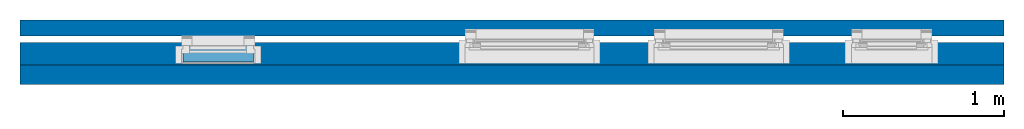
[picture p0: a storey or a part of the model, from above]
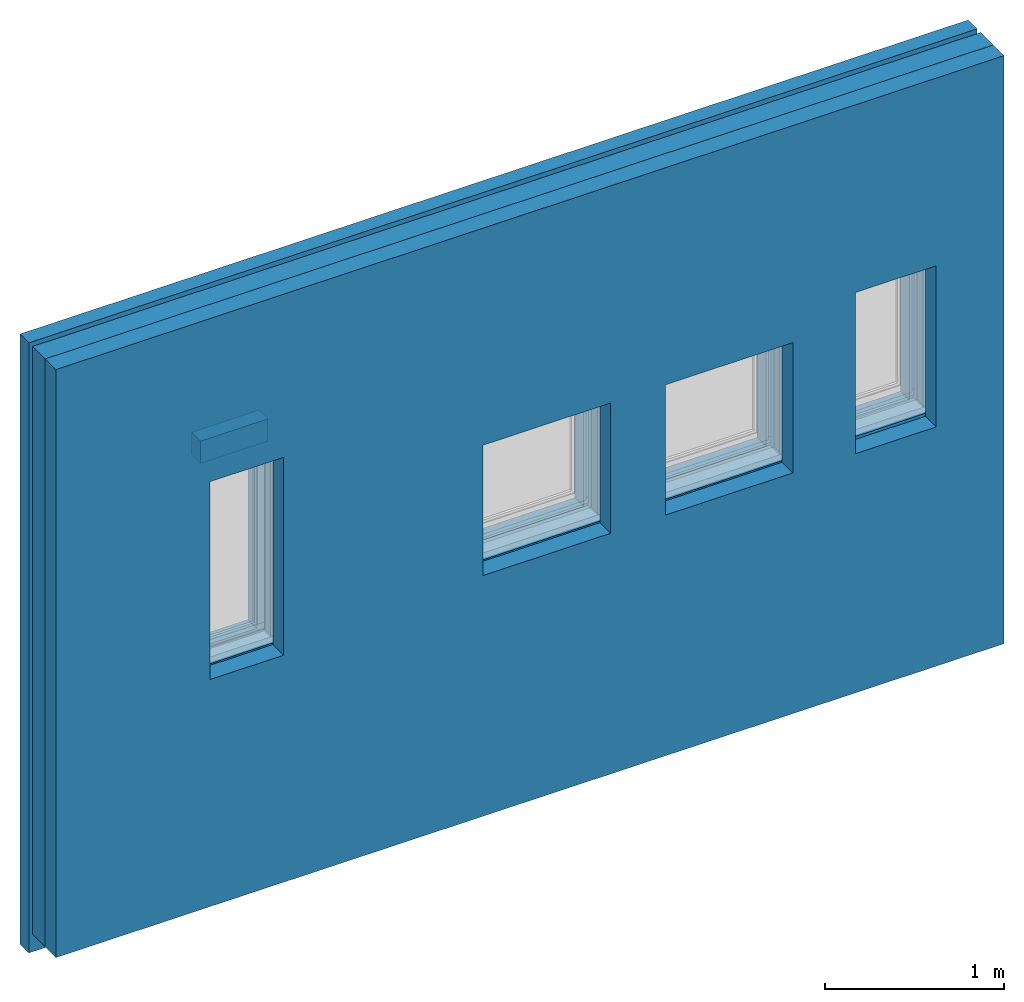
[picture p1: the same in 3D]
Properties of the parts of a building model (IFC2X3)

# File
Description: ViewDefinition [CoordinationView_V2.0]
File name: 0001
Time: 2018-10-30T14:35:21
Written by: The EXPRESS Data Manager Version 5.02.0100.07 : 28 Aug 2013
Made in: 20180328_1600(x64) - Exporter 19.1.0.0 - Alternate UI 19.1.0.0
Comment: STEP Physical File produced by: The EXPRESS Data Manager Version 5.02.0100.07 : 28 Aug 2013 * Module: EDMstepFileFactory/EDMstandAlone * Creation date: Tue Oct 30 14:35:21 2018 * Host: DESKTOP-FDA31SE * Database: C:\Users\marti\AppData\Local\Temp\{E08C83BA-BC12-497E-8B5D-7DDBD25FC910}\ifc * Database version: 5507 * Database creation date: Tue Oct 30 14:35:19 2018 * Schema: IFC2X3 * Model: DataRepository.ifc * Model creation date: Tue Oct 30 14:35:19 2018 * Header model: DataRepository.ifc_HeaderModel * Header model creation date: Tue Oct 30 14:35:20 2018 * EDMuser: sdai-user * EDMgroup: sdai-group * License ID and type: 5605 : Permanent license. Expiry date: * EDMstepFileFactory options: 020000

# IfcProject, 0001
LongName: Project Name; Phase: Project Status

# IfcSite, Default
RefLatitude: 42, 21, 31, 181945; RefLongitude: -71, -3, -24, -263305; RefElevation: 0 mm

# IfcBuilding
Pset_BuildingCommon - NumberOfStoreys: 1
Pset_ProductRequirements - Category: Project Information

# IfcBuildingStorey: Level:8mm Head, Level 1
LongName: Level 1; Elevation: 0 mm
Pset_AirSideSystemInformation - Name: Level 1
Pset_ProductRequirements - Name: Level 1; Category: Levels

# IfcElementAssembly: NLRS_31_WI_H11_A1vg_GM:455 breed, NLRS_31_WI_H11_A1vg_GM:455 breed:395825
In: Level 1
Classification: 31.22.21 (Uniformat); Group: Model Group:NLRS_31_WI_H11_A1vg_GM - 455 breed:418941
Pset_ProductRequirements - Category: Windows
Pset_QuantityTakeOff - Reference: 455 breed

# IfcElementAssembly: Windows Assembly:NLRS_31_WI_H11-A1dr-GM_sh_gen_TOBA-JM - Kozijn tbv IFC 800x800, Windows Assembly:NLRS_31_WI_H11-A1dr-GM_sh_gen_TOBA-JM - Kozijn tbv IFC 800x800:418976
In: Level 1
PredefinedType: USERDEFINED
Pset_ProductRequirements - Category: Assemblies
Pset_QuantityTakeOff - Reference: NLRS_31_WI_H11-A1dr-GM_sh_gen_TOBA-JM - Kozijn tbv IFC 800x800

# IfcOpeningElement: Opening (12)
In: Level 1
Pset_ElementShading - Roughness: 304.8 mm
Pset_ManufacturerTypeInformation - Manufacturer: TOBA b.v.
Pset_ProductRequirements - Category: Walls
Pset_QuantityTakeOff - sets with these values: 2
Name (Basic Wall:...) | Classification | Reference
4 x NLRS_21_WA_metselwerk bestaand 100mm:343451 | 21.11 buitenwanden; niet constructief, massieve wanden (Uniformat) | NLRS_21_WA_metselwerk bestaand 100mm
4 x NLRS_21_WA_isolatie_EPS 140mm:343452 | 21.00 (Uniformat) | NLRS_21_WA_isolatie_EPS 140mm
4 x NLRS_21_WA_kalkzandsteen CS12 120mm:359981 | 21.21 buitenwanden; constructief, massieve wanden (Uniformat) | NLRS_21_WA_kalkzandsteen CS12 120mm

# IfcWallStandardCase: Basic Wall:NLRS_21_WA_isolatie_EPS 140mm, Basic Wall:NLRS_21_WA_isolatie_EPS 140mm:343452
In: Level 1
Type - PredefinedType: STANDARD; Material: NLRS_n7_isolatie_EPS_140mm 140 mm
Type - Pset_ElementShading - Roughness: 304.8 mm
Type - Pset_ManufacturerTypeInformation - Manufacturer: TOBA b.v.
Type - Pset_ProductRequirements - Category: Walls
Type - Pset_QuantityTakeOff - Reference: NLRS_21_WA_isolatie_EPS 140mm
Type - Pset_ReinforcementBarPitchOfWall - Description: isolatie, EPS; Reference: NLRS_21_WA_isolatie_EPS 140mm
Type - Pset_WallCommon - IsExternal: no; Reference: NLRS_21_WA_isolatie_EPS 140mm; ThermalTransmittance: 0.25 kg/K/s3
Classification: 21.00 (Uniformat)
Pset_WallCommon - IsExternal: yes; ExtendToStructure: no; LoadBearing: no

# IfcWallStandardCase: Basic Wall:NLRS_21_WA_kalkzandsteen CS12 120mm, Basic Wall:NLRS_21_WA_kalkzandsteen CS12 120mm:359981
In: Level 1
Type - PredefinedType: STANDARD; Material: NLRS_f1_kalkzandsteen_CS12 120 mm
Type - Pset_ElementShading - Roughness: 304.8 mm
Type - Pset_ManufacturerTypeInformation - Manufacturer: TOBA b.v.
Type - Pset_ProductRequirements - Category: Walls
Type - Pset_QuantityTakeOff - Reference: NLRS_21_WA_kalkzandsteen CS12 120mm
Type - Pset_ReinforcementBarPitchOfWall - Description: binnenspouwblad kalkzandsteen; Reference: NLRS_21_WA_kalkzandsteen CS12 120mm
Type - Pset_WallCommon - IsExternal: no; Reference: NLRS_21_WA_kalkzandsteen CS12 120mm; ThermalTransmittance: 7.16667 kg/K/s3
Classification: 21.21 buitenwanden; constructief, massieve wanden (Uniformat)
Pset_WallCommon - IsExternal: yes; ExtendToStructure: no; LoadBearing: no

# IfcWallStandardCase: Basic Wall:NLRS_21_WA_metselwerk bestaand 100mm, Basic Wall:NLRS_21_WA_metselwerk bestaand 100mm:343451
In: Level 1
Type - PredefinedType: STANDARD; Material: NLRS_g2_baksteen_bestaand 100 mm
Type - Pset_ElementShading - Roughness: 304.8 mm
Type - Pset_ManufacturerTypeInformation - Manufacturer: TOBA b.v.
Type - Pset_ProductRequirements - Category: Walls
Type - Pset_QuantityTakeOff - Reference: NLRS_21_WA_metselwerk bestaand 100mm
Type - Pset_ReinforcementBarPitchOfWall - Description: bestaande buitenwand, halfsteens metselwerk; Reference: NLRS_21_WA_metselwerk bestaand 100mm
Type - Pset_WallCommon - Reference: NLRS_21_WA_metselwerk bestaand 100mm; ThermalTransmittance: 4.1 kg/K/s3; IsExternal: no
Classification: 21.11 buitenwanden; niet constructief, massieve wanden (Uniformat)
Pset_WallCommon - IsExternal: yes; ExtendToStructure: no; LoadBearing: no

# IfcWindow: 17x17 (3)
In: Level 1
Type - ParameterTakesPrecedence: no; Sizeable: no; Classification: 31 Buitenwandopeningen (Uniformat); Material: NLRS_i3_meranti_draaiende_delen_geschilderd_creme_RAL7006
Pset_ProductRequirements - Category: Windows
Pset_QuantityTakeOff - Reference: 17x17
Pset_WindowCommon - IsExternal: no; Reference: 17x17
Name (NLRS_30_WIN_glaslat-raam_sh_gen_TOBA-JM:17x17:...) | OverallHeight (mm) | OverallWidth (mm)
345039 | 666 | 666
360892 | 666 | 666
360925 | 866 | 366 | Group: Model Group:NLRS_31_WI_H11-A1dr-GM_sh_gen_TOBA-JM - Raam tbv IFC Export 1000x500:418978

# IfcWindow: 43x145 (3)
In: Level 1
Type - ParameterTakesPrecedence: no; Sizeable: no; Classification: 31 Buitenwandopeningen (Uniformat); Material: NLRS_i3_hout_vuren_generiek
OverallHeight: 44.8059 mm
Pset_ProductRequirements - Category: Windows
Pset_QuantityTakeOff - Reference: 43x145
Pset_WindowCommon - IsExternal: no; Reference: 43x145
Name (NLRS_30_WIN_spouwlat_bovendorpel-zonder-bovenrek_sh_gen_TOBA-JM:43x145:...) | OverallWidth (mm)
345042 | 876
360895 | 876
360928 | 576 | Group: Model Group:NLRS_31_WI_H11-A1dr-GM_sh_gen_TOBA-JM - Raam tbv IFC Export 1000x500:418978

# IfcWindow: 53x145 (3)
In: Level 1
Type - ParameterTakesPrecedence: no; Sizeable: no; Classification: 31 Buitenwandopeningen (Uniformat); Material: NLRS_i3_hout_vuren_generiek
OverallHeight: 53 mm
Pset_ProductRequirements - Category: Windows
Pset_QuantityTakeOff - Reference: 53x145
Pset_WindowCommon - IsExternal: no; Reference: 53x145
Name (NLRS_30_WIN_spouwlat-onderdorpel_sh_gen_TOBA-JM:53x145:...) | OverallWidth (mm)
345034 | 876
360887 | 876
360920 | 576 | Group: Model Group:NLRS_31_WI_H11-A1dr-GM_sh_gen_TOBA-JM - Raam tbv IFC Export 1000x500:418978

# IfcWindow: 68x90 (3)
In: Level 1
Type - ParameterTakesPrecedence: no; Sizeable: no; Classification: 31 Buitenwandopeningen (Uniformat); Material: NLRS_i3_meranti_draaiende_delen_geschilderd_creme_RAL7006
Pset_ProductRequirements - Category: Windows
Pset_QuantityTakeOff - Reference: 68x90
Pset_WindowCommon - IsExternal: no; Reference: 68x90
Name (NLRS_30_WIN_raamhout_sh_gen_TOBA-JM:68x90:...) | OverallHeight (mm) | OverallWidth (mm)
345038 | 715 | 752
360891 | 715 | 752
360924 | 915 | 452 | Group: Model Group:NLRS_31_WI_H11-A1dr-GM_sh_gen_TOBA-JM - Raam tbv IFC Export 1000x500:418978

# IfcWindow: Type, NLRS_30_MC_aftimmering_rekje:Type:406789
In: Level 1
Type - ParameterTakesPrecedence: no; Sizeable: no; Classification: 31 Buitenwandopeningen (Uniformat); Material: NLRS_f7_gips_vertikaal
OverallHeight: 230 mm; OverallWidth: 437 mm; Group: Model Group:NLRS_31_WI_H11_A1vg_GM - 455 breed:418941
Pset_ProductRequirements - Category: Windows
Pset_QuantityTakeOff - Reference: Type
Pset_WindowCommon - IsExternal: no; Reference: Type

# IfcWindow: Type (5)
In: Level 1
Type - ParameterTakesPrecedence: no; Sizeable: no; Classification: 31 Buitenwandopeningen (Uniformat); Material: NLRS_i3_hout_vuren_generiek
Pset_ProductRequirements - Category: Windows
Pset_QuantityTakeOff - Reference: Type
Pset_WindowCommon - IsExternal: no; Reference: Type
Group: Model Group:NLRS_31_WI_H11_A1vg_GM - 455 breed:418941
Name | OverallHeight (mm) | OverallWidth (mm)
NLRS_30_MC_spouwlat_zijstijll_47x110:Type:395856 | 1527.4 | 105
NLRS_30_MC_spouwlat_onderdorpel_bis_53x110:Type:406786 | 53 | 531
NLRS_30_MC_spouwlat_zijstijll_47x110:Type:406787 | 1527.4 | 105
NLRS_30_MC_spouwlat_bovendorpel_bis_38x101:Type:406788 | 38 | 437
NLRS_30_MC_spouwlat_bovendorpel_boven_rekje_bis_45x101:Type:406790 | 45.026 | 437

# IfcWindow: Type (4)
In: Level 1
Type - ParameterTakesPrecedence: no; Sizeable: no; Classification: 31 Buitenwandopeningen (Uniformat); Material: NLRS_i3_meranti_geschilderd_RAL7006
Pset_ProductRequirements - Category: Windows
Pset_QuantityTakeOff - Reference: Type
Pset_WindowCommon - IsExternal: no; Reference: Type
Group: Model Group:NLRS_31_WI_H11_A1vg_GM - 455 breed:418941
Name | OverallHeight (mm) | OverallWidth (mm)
NLRS_30_MC_onderdorpel_bis_67x114:Type:395826 | 67 | 455
NLRS_30_MC_zijstijll_vg_bis_67x114:Type:395827 | 1274.4 | 67
NLRS_30_MC_zijstijll_vg_bis_67x114:Type:395828 | 1274.4 | 67
NLRS_30_MC_bovendorpel_vg_bis_90x114:Type:395857 | 90 | 455

# IfcWindow: aanslagprofiel (3)
In: Level 1
Type - ParameterTakesPrecedence: no; Sizeable: no; Classification: 31 Buitenwandopeningen (Uniformat); Material: NLRS_h4_aluminum_geanodizeerd_RAL7006
Pset_ProductRequirements - Category: Windows
Pset_QuantityTakeOff - Reference: aanslagprofiel
Pset_WindowCommon - IsExternal: no; Reference: aanslagprofiel
Name (NLRS_30_WIN_aanslagprofiel_sh_gen_TOBA-JM:aanslagprofiel:...) | OverallHeight (mm) | OverallWidth (mm)
345040 | 671.5 | 666
360893 | 671.5 | 666
360926 | 871.5 | 366 | Group: Model Group:NLRS_31_WI_H11-A1dr-GM_sh_gen_TOBA-JM - Raam tbv IFC Export 1000x500:418978

# IfcWindow: bis-67x114 (3)
In: Level 1
Type - ParameterTakesPrecedence: no; Sizeable: no; Classification: 31 Buitenwandopeningen (Uniformat); Material: NLRS_i3_meranti_geschilderd_RAL7006
OverallHeight: 67 mm
Pset_ProductRequirements - Category: Windows
Pset_QuantityTakeOff - Reference: bis-67x114
Pset_WindowCommon - IsExternal: no; Reference: bis-67x114
Name (NLRS_30_WIN_onderdorpel_sh_gen_TOBA-JM:bis-67x114:...) | OverallWidth (mm)
345031 | 800
360884 | 800
360917 | 500 | Group: Model Group:NLRS_31_WI_H11-A1dr-GM_sh_gen_TOBA-JM - Raam tbv IFC Export 1000x500:418978

# IfcWindow: dv-bis-67x114 (3)
In: Level 1
Type - ParameterTakesPrecedence: no; Sizeable: no; Classification: 31 Buitenwandopeningen (Uniformat); Material: NLRS_i3_meranti_geschilderd_RAL7006
OverallHeight: 67 mm
Pset_ProductRequirements - Category: Windows
Pset_QuantityTakeOff - Reference: dv-bis-67x114
Pset_WindowCommon - IsExternal: no; Reference: dv-bis-67x114
Name (NLRS_30_WIN_bovendorpel_sh_gen_TOBA-JM:dv-bis-67x114:...) | OverallWidth (mm)
345036 | 800
360889 | 800
360922 | 500 | Group: Model Group:NLRS_31_WI_H11-A1dr-GM_sh_gen_TOBA-JM - Raam tbv IFC Export 1000x500:418978

# IfcWindow: dv-bis67x114 (6)
In: Level 1
Type - ParameterTakesPrecedence: no; Sizeable: no; Classification: 31 Buitenwandopeningen (Uniformat); Material: NLRS_i3_meranti_geschilderd_RAL7006
OverallWidth: 67 mm
Pset_ProductRequirements - Category: Windows
Pset_QuantityTakeOff - Reference: dv-bis67x114
Pset_WindowCommon - IsExternal: no; Reference: dv-bis67x114
Name (NLRS_30_WIN_zijstijl_sh_gen_TOBA-JM:dv-bis67x114:...) | OverallHeight (mm)
345032 | 761.7
345033 | 761.7
360885 | 761.7
360886 | 761.7
360918 | 961.7 | Group: Model Group:NLRS_31_WI_H11-A1dr-GM_sh_gen_TOBA-JM - Raam tbv IFC Export 1000x500:418978
360919 | 961.7 | Group: Model Group:NLRS_31_WI_H11-A1dr-GM_sh_gen_TOBA-JM - Raam tbv IFC Export 1000x500:418978

# IfcWindow: isolerend-raam (3)
In: Level 1
Type - ParameterTakesPrecedence: no; Sizeable: no; Classification: 31 Buitenwandopeningen (Uniformat); Material: NLRS_o2_glas_mat
Pset_ProductRequirements - Category: Windows
Pset_QuantityTakeOff - Reference: isolerend-raam
Pset_WindowCommon - IsExternal: no; Reference: isolerend-raam
Name (NLRS_30_WIN_glas-isolerend-raam_sh_gen_TOBA-JM:isolerend-raam:...) | OverallHeight (mm) | OverallWidth (mm)
345041 | 666 | 666
360894 | 666 | 666
360927 | 866 | 366 | Group: Model Group:NLRS_31_WI_H11-A1dr-GM_sh_gen_TOBA-JM - Raam tbv IFC Export 1000x500:418978

# IfcWindow: ok-bk-recht-45x145 (6)
In: Level 1
Type - ParameterTakesPrecedence: no; Sizeable: no; Classification: 31 Buitenwandopeningen (Uniformat); Material: NLRS_i3_hout_vuren_generiek
OverallWidth: 105 mm
Pset_ProductRequirements - Category: Windows
Pset_QuantityTakeOff - Reference: ok-bk-recht-45x145
Pset_WindowCommon - IsExternal: no; Reference: ok-bk-recht-45x145
Name (NLRS_30_WIN_spouwlat-zijstijll_sh_gen_TOBA-JM:ok-bk-recht-45x145:...) | OverallHeight (mm)
345035 | 800
345037 | 800
360888 | 800
360890 | 800
360921 | 1000 | Group: Model Group:NLRS_31_WI_H11-A1dr-GM_sh_gen_TOBA-JM - Raam tbv IFC Export 1000x500:418978
360923 | 1000 | Group: Model Group:NLRS_31_WI_H11-A1dr-GM_sh_gen_TOBA-JM - Raam tbv IFC Export 1000x500:418978

# IfcWindow: type, NLRS_30_MC_beglazingsprofiel_aluminium:type:406792
In: Level 1
Type - ParameterTakesPrecedence: no; Sizeable: no; Classification: 31 Buitenwandopeningen (Uniformat); Material: NLRS_h4_aluminum_geanodizeerd_RAL7006
OverallHeight: 1162.9 mm; OverallWidth: 355 mm; Group: Model Group:NLRS_31_WI_H11_A1vg_GM - 455 breed:418941
Pset_ProductRequirements - Category: Windows
Pset_QuantityTakeOff - Reference: type
Pset_WindowCommon - IsExternal: no; Reference: type

# IfcWindow: type, NLRS_30_MC_glaslat_vast_17x17:type:406791
In: Level 1
Type - ParameterTakesPrecedence: no; Sizeable: no; Classification: 31 Buitenwandopeningen (Uniformat); Material: NLRS_i3_meranti_geschilderd_RAL7006
OverallHeight: 1157.4 mm; OverallWidth: 355 mm; Group: Model Group:NLRS_31_WI_H11_A1vg_GM - 455 breed:418941
Pset_ProductRequirements - Category: Windows
Pset_QuantityTakeOff - Reference: type
Pset_WindowCommon - IsExternal: no; Reference: type

# IfcWindow: type, NLRS_30_MC_glas_isolerend_vast:type:406793
In: Level 1
Type - ParameterTakesPrecedence: no; Sizeable: no; Classification: 31 Buitenwandopeningen (Uniformat); Material: NLRS_o2_glas_mat
OverallHeight: 1157.4 mm; OverallWidth: 355 mm; Group: Model Group:NLRS_31_WI_H11_A1vg_GM - 455 breed:418941
Pset_ProductRequirements - Category: Windows
Pset_QuantityTakeOff - Reference: type
Pset_WindowCommon - IsExternal: no; Reference: type
